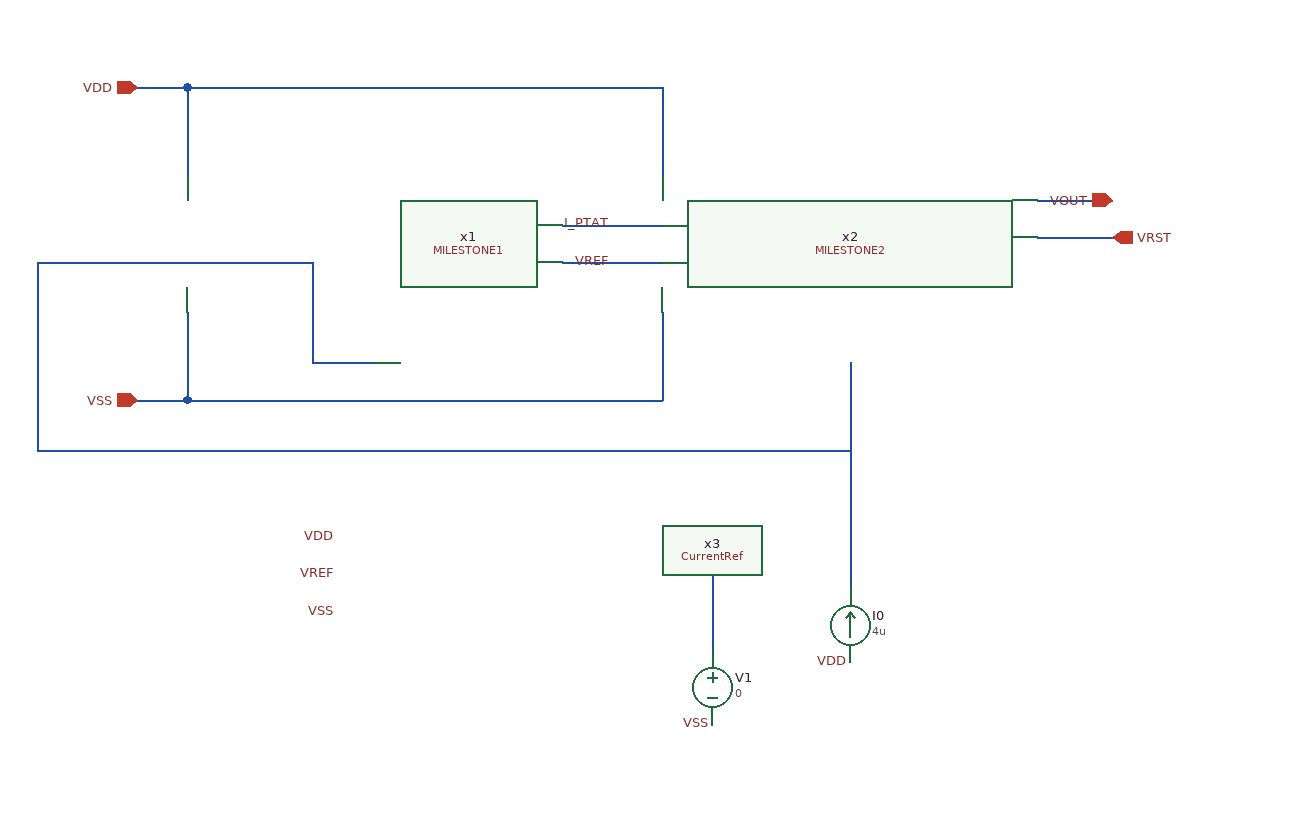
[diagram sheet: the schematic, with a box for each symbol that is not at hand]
v {xschem version=3.4.4 file_version=1.2
}
G {}
K {}
V {}
S {}
E {}
N -40 -110 40 -110 {
lab=I_PTAT}
N -40 -80 40 -80 {
lab=VREF}
N -380 -220 -350 -220 {
lab=VDD}
N -350 -220 -340 -220 {
lab=VDD}
N -340 -220 -340 -210 {
lab=VDD}
N -340 -210 -340 -200 {
lab=VDD}
N -340 -200 -340 -190 {
lab=VDD}
N -340 -190 -340 -180 {
lab=VDD}
N -340 -180 -340 -170 {
lab=VDD}
N -340 -170 -340 -160 {
lab=VDD}
N -340 -160 -340 -150 {
lab=VDD}
N -340 10 -340 20 {
lab=VSS}
N -340 -0 -340 10 {
lab=VSS}
N -340 -10 -340 -0 {
lab=VSS}
N -340 -20 -340 -10 {
lab=VSS}
N -340 -30 -340 -20 {
lab=VSS}
N -340 -40 -340 -30 {
lab=VSS}
N -340 -220 -280 -220 {
lab=VDD}
N -280 -220 -270 -220 {
lab=VDD}
N -270 -220 -260 -220 {
lab=VDD}
N -260 -220 -250 -220 {
lab=VDD}
N -250 -220 -240 -220 {
lab=VDD}
N -240 -220 -230 -220 {
lab=VDD}
N -230 -220 -220 -220 {
lab=VDD}
N -220 -220 -210 -220 {
lab=VDD}
N -210 -220 -200 -220 {
lab=VDD}
N -200 -220 -190 -220 {
lab=VDD}
N -190 -220 -180 -220 {
lab=VDD}
N -180 -220 -170 -220 {
lab=VDD}
N -170 -220 -160 -220 {
lab=VDD}
N -160 -220 -150 -220 {
lab=VDD}
N -150 -220 -140 -220 {
lab=VDD}
N -140 -220 -130 -220 {
lab=VDD}
N -130 -220 -120 -220 {
lab=VDD}
N -120 -220 -110 -220 {
lab=VDD}
N -110 -220 -100 -220 {
lab=VDD}
N -100 -220 -90 -220 {
lab=VDD}
N -90 -220 -80 -220 {
lab=VDD}
N -80 -220 -70 -220 {
lab=VDD}
N -70 -220 -60 -220 {
lab=VDD}
N -60 -220 -50 -220 {
lab=VDD}
N -50 -220 -40 -220 {
lab=VDD}
N -40 -220 -30 -220 {
lab=VDD}
N -30 -220 -20 -220 {
lab=VDD}
N -20 -220 -10 -220 {
lab=VDD}
N -10 -220 -0 -220 {
lab=VDD}
N -0 -220 10 -220 {
lab=VDD}
N 10 -220 20 -220 {
lab=VDD}
N 20 -220 30 -220 {
lab=VDD}
N 30 -220 40 -220 {
lab=VDD}
N 40 -220 40 -210 {
lab=VDD}
N 40 -210 40 -200 {
lab=VDD}
N 40 -200 40 -190 {
lab=VDD}
N 40 -190 40 -180 {
lab=VDD}
N 40 -180 40 -170 {
lab=VDD}
N 40 -170 40 -160 {
lab=VDD}
N 40 -160 40 -150 {
lab=VDD}
N 40 10 40 20 {
lab=VSS}
N 40 -0 40 10 {
lab=VSS}
N 40 -10 40 -0 {
lab=VSS}
N 40 -20 40 -10 {
lab=VSS}
N 40 -30 40 -20 {
lab=VSS}
N 40 -40 40 -30 {
lab=VSS}
N -380 30 -340 30 {
lab=VSS}
N -340 20 -340 30 {
lab=VSS}
N -340 30 -310 30 {
lab=VSS}
N -310 30 -300 30 {
lab=VSS}
N -300 30 -290 30 {
lab=VSS}
N -290 30 -280 30 {
lab=VSS}
N -280 30 -270 30 {
lab=VSS}
N -270 30 -260 30 {
lab=VSS}
N -260 30 -250 30 {
lab=VSS}
N -250 30 -240 30 {
lab=VSS}
N -240 30 -230 30 {
lab=VSS}
N -230 30 -220 30 {
lab=VSS}
N -220 30 -210 30 {
lab=VSS}
N -210 30 -200 30 {
lab=VSS}
N -200 30 -190 30 {
lab=VSS}
N -190 30 -180 30 {
lab=VSS}
N -180 30 -170 30 {
lab=VSS}
N -170 30 -160 30 {
lab=VSS}
N -160 30 -150 30 {
lab=VSS}
N -150 30 -140 30 {
lab=VSS}
N -140 30 -130 30 {
lab=VSS}
N -130 30 -120 30 {
lab=VSS}
N -120 30 -110 30 {
lab=VSS}
N -110 30 -100 30 {
lab=VSS}
N -100 30 -90 30 {
lab=VSS}
N -90 30 -80 30 {
lab=VSS}
N -80 30 -70 30 {
lab=VSS}
N -70 30 -60 30 {
lab=VSS}
N -60 30 -50 30 {
lab=VSS}
N -50 30 -40 30 {
lab=VSS}
N -40 30 -30 30 {
lab=VSS}
N -30 30 -20 30 {
lab=VSS}
N -20 30 -10 30 {
lab=VSS}
N -10 30 -0 30 {
lab=VSS}
N 0 30 10 30 {
lab=VSS}
N 10 30 20 30 {
lab=VSS}
N 20 30 30 30 {
lab=VSS}
N 30 30 40 30 {
lab=VSS}
N 40 20 40 30 {
lab=VSS}
N 340 -130 400 -130 {
lab=VOUT}
N 340 -100 400 -100 {
lab=VRST}
N 80 170 80 230 {
lab=#net1}
N -190 70 190 70 {
lab=VSS}
N 190 0 190 70 {
lab=VSS}
N 190 0 190 180 {
lab=VSS}
N -240 0 -190 0 {}
N -240 -80 -240 0 {}
N -460 -80 -240 -80 {}
N -460 -80 -460 70 {}
N -460 70 -190 70 {}
C {CNR_GR03_SKY130NM/MILESTONE1.sym} -190 -120 0 0 {name=x1}
C {CNR_GR03_SKY130NM/MILESTONE2.sym} 190 -100 0 0 {name=x2}
C {devices/ipin.sym} -380 -220 0 0 {name=p1 lab=VDD}
C {devices/ipin.sym} -380 30 0 0 {name=p2 lab=VSS}
C {devices/opin.sym} 400 -130 2 1 {name=p3 lab=VOUT}
C {devices/ipin.sym} 400 -100 0 1 {name=p4 lab=VRST}
C {devices/lab_wire.sym} 0 -110 0 0 {name=p5 sig_type=std_logic lab=I_PTAT}
C {devices/lab_wire.sym} 0 -80 0 0 {name=p6 sig_type=std_logic lab=VREF}
C {CNR_GR03_SKY130NM/CurrentRef.sym} -70 170 0 0 {name=x3
}
C {devices/lab_wire.sym} -220 170 0 0 {name=p7 sig_type=std_logic lab=VREF}
C {devices/lab_wire.sym} -220 140 0 0 {name=p8 sig_type=std_logic lab=VDD}
C {devices/lab_wire.sym} -220 200 0 0 {name=p9 sig_type=std_logic lab=VSS}
C {devices/vsource.sym} 80 260 0 0 {name=V1 value=0 savecurrent=false}
C {devices/lab_wire.sym} 80 290 0 0 {name=p10 sig_type=std_logic lab=VSS}
C {devices/isource.sym} 190 210 2 0 {name=I0 value=4u}
C {devices/lab_wire.sym} 190 240 0 0 {name=p11 sig_type=std_logic lab=VDD}
